VERSION 5.8 ;
BUSBITCHARS "[]" ;
DIVIDERCHAR "/" ;
CLEARANCEMEASURE EUCLIDEAN ;

SITE coresite_DH_P
    SIZE 0.0450 BY 0.2880 ;
    CLASS CORE ;
    SYMMETRY X Y ;
END coresite_DH_P

SITE coresite_DH_N
    SIZE 0.0450 BY 0.2880 ;
    CLASS CORE ;
    SYMMETRY X Y ;
END coresite_DH_N

SITE coresite
    SIZE 0.0450 BY 0.1440 ;
    CLASS CORE ;
    SYMMETRY X Y ;
END coresite

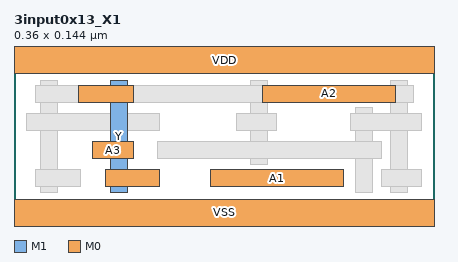
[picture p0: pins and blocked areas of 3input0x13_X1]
MACRO 3input0x13_X1
  CLASS CORE ;
  ORIGIN 0 0 ;
  FOREIGN 3input0x13_X1 0 0 ;
  SIZE 0.3600 BY 0.1440 ;
  SYMMETRY X Y ;
  SITE coresite ;
  PIN Y
    DIRECTION OUTPUT ;
    USE SIGNAL ;
    PORT
      LAYER M1 ;
        RECT 0.0825 0.1200 0.0975 0.0240 ;
      LAYER M0 ;
        RECT 0.0780 0.0430 0.1245 0.0290 ;
        RECT 0.0555 0.1150 0.1020 0.1010 ;
    END
  END Y
  PIN A1
    DIRECTION INPUT ;
    USE SIGNAL ;
    PORT
      LAYER M0 ;
        RECT 0.1680 0.0430 0.2820 0.0290 ;
    END
  END A1
  PIN A3
    DIRECTION INPUT ;
    USE SIGNAL ;
    PORT
      LAYER M0 ;
        RECT 0.0675 0.0670 0.1020 0.0530 ;
    END
  END A3
  PIN A2
    DIRECTION INPUT ;
    USE SIGNAL ;
    PORT
      LAYER M0 ;
        RECT 0.2130 0.1150 0.3270 0.1010 ;
    END
  END A2
  PIN VDD
    DIRECTION INOUT ;
    USE POWER ;
    SHAPE ABUTMENT ;
    PORT
      LAYER M0 ;
        RECT 0.0000 0.1260 0.3600 0.1620 ;
    END
  END VDD
  PIN VSS
    DIRECTION INOUT ;
    USE GROUND ;
    SHAPE ABUTMENT ;
    PORT
      LAYER M0 ;
        RECT 0.0000 -0.0180 0.3600 0.0180 ;
    END
  END VSS
  OBS
      LAYER V0 ;
        RECT 0.2930 0.0770 0.3070 0.0910 ;
        RECT 0.2930 0.0530 0.3070 0.0670 ;
        RECT 0.0830 0.1010 0.0970 0.1150 ;
        RECT 0.0830 0.0290 0.0970 0.0430 ;
        RECT 0.0230 0.0290 0.0370 0.0430 ;
        RECT 0.2030 0.0770 0.2170 0.0910 ;
        RECT 0.3230 0.0290 0.3370 0.0430 ;
      LAYER M1 ;
        RECT 0.2925 0.0960 0.3075 0.0240 ;
        RECT 0.0225 0.1200 0.0375 0.0240 ;
        RECT 0.2025 0.1200 0.2175 0.0480 ;
        RECT 0.3225 0.1200 0.3375 0.0240 ;
      LAYER V1 ;
        RECT 0.0230 0.1010 0.0370 0.1150 ;
        RECT 0.2030 0.1010 0.2170 0.1150 ;
        RECT 0.3230 0.1010 0.3370 0.1150 ;
      LAYER M2 ;
        RECT 0.0180 0.1010 0.3420 0.1150 ;
      LAYER M0 ;
        RECT 0.0180 0.0290 0.0570 0.0430 ;
        RECT 0.3150 0.0290 0.3495 0.0430 ;
        RECT 0.1230 0.0530 0.3150 0.0670 ;
        RECT 0.0105 0.0770 0.1245 0.0910 ;
        RECT 0.1905 0.0770 0.2250 0.0910 ;
        RECT 0.2880 0.0770 0.3495 0.0910 ;
  END
END 3input0x13_X1

END LIBRARY
